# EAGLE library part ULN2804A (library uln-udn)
DRIVER ARRAY

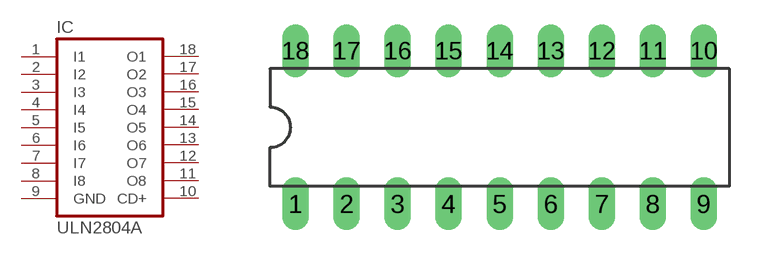
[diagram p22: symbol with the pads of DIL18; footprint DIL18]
Designator prefix IC

## ULN2804A  [DIL18]
1  I1  in
2  I2  in
3  I3  in
4  I4  in
5  I5  in
6  I6  in
7  I7  in
8  I8  in
9  GND  pwr
10  CD+  pas
11  O8  oc
12  O7  oc
13  O6  oc
14  O5  oc
15  O4  oc
16  O3  oc
17  O2  oc
18  O1  oc

## Footprint DIL18 (pad centres in mm)
Dual In Line Package
drill 0.813 long: 1 -10.16,-3.81; 2 -7.62,-3.81; 3 -5.08,-3.81; 4 -2.54,-3.81; 5 0,-3.81; 6 2.54,-3.81; 7 5.08,-3.81; 8 7.62,-3.81; 9 10.16,-3.81; 10 10.16,3.81; 11 7.62,3.81; 12 5.08,3.81; 13 2.54,3.81; 14 0,3.81; 15 -2.54,3.81; 16 -5.08,3.81; 17 -7.62,3.81; 18 -10.16,3.81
